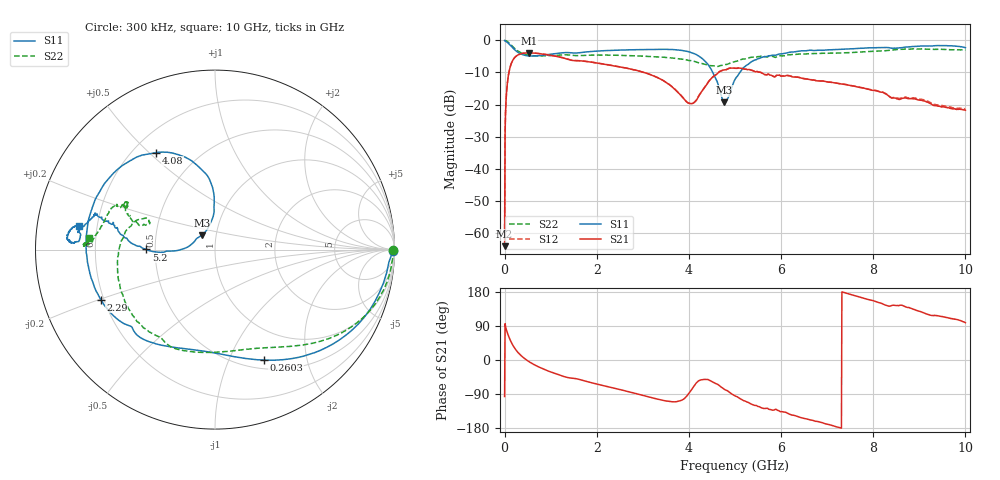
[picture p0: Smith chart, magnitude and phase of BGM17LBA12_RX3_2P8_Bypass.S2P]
!Agilent Technologies,E5071C,MY46316587,B.13.01
!Date: Fri Dec 08 10:57:01 2017
!Data & Calibration Information:
!Freq	S11:SOLT2(ON)	S21:SOLT2(ON)	S12:SOLT2(ON)	S22:SOLT2(ON)
!PortZ  Port1:50+j0  Port2:50+j0
!Above PortZ is port z conversion or system Z0 setting when saving the data.
!When reading, reference impedance value at option line is always used.
# Hz S dB R 50
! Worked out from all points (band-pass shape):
!   1001 points, 300 kHz to 10 GHz, reference 50 ohm
!   highest |S21| = -3.92 dB at 530.3 MHz (marker M1); lowest = -63.9 dB at 300 kHz (marker M2)
!   |S21| within 3 dB of the highest: 154.2 MHz to 1.932 GHz (1.777 GHz wide, 170 % of centre)
!   lowest |S11| = -19.3 dB at 4.77 GHz (marker M3), VSWR 1.24, Z = 42.7 + j6.97 ohm
!   |S11| at or under -10 dB: 4.518 GHz to 5.105 GHz (587.2 MHz wide, 12.2 % of centre)
!   |S22| runs from -8.2 to -0.1 dB; largest |S21 - S12| = 0.0059
!   S11 on the Smith chart (normalised r, x): 300 kHz: open; 260.3 MHz: 0.60, -1.35; 2.29 GHz: 0.19, -0.20; 4.08 GHz: 0.29, +0.53; 5.2 GHz: 0.45, +0.00; 10 GHz: 0.13, +0.09
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300000  -0.07 -0.3  -63.94 -96.5  -58.58 165.9  -0.06 -0.2
6.02982e7  -0.67 -21.2  -13.33 71.7  -13.25 71.8  -0.40 -16.0
7.02979e7  -0.79 -24.3  -12.11 68.3  -12.05 68.3  -0.50 -18.4
1.402958e8  -1.80 -43.6  -7.42 47.8  -7.38 47.7  -1.45 -33.1
2.602922e8  -3.45 -66.3  -4.85 24.3  -4.82 24.1  -3.06 -49.5
5.302841e8  -4.86 -93.5  -3.92 -4.4  -3.90 -4.5  -4.65 -71.5
1.030269e9  -4.28 -119.5  -4.75 -33.0  -4.73 -33.1  -4.73 -99.7
1.67025e9  -3.79 -139.5  -6.42 -52.9  -6.37 -52.9  -4.74 -123.8
2.290231e9  -3.16 -156.4  -7.74 -71.9  -7.72 -71.7  -4.63 -140.3
3.3402e9  -2.81 165.0  -11.74 -103.8  -11.76 -103.4  -5.19 -170.7
3.720188e9  -2.97 144.8  -15.60 -110.1  -15.55 -109.8  -5.61 174.6
4.080178e9  -3.98 121.3  -19.62 -74.2  -19.54 -74.0  -6.43 161.4
4.440167e9  -8.04 94.7  -12.57 -53.2  -12.58 -52.9  -7.86 156.0
4.770157e9  -19.28 132.1  -9.19 -77.5  -9.20 -77.5  -7.62 160.5
4.850154e9  -17.91 162.6  -8.84 -82.5  -8.82 -82.4  -7.35 161.6
5.00015e9  -12.16 -178.1  -8.72 -94.7  -8.70 -94.6  -6.63 160.8
5.200144e9  -8.33 179.9  -8.99 -107.7  -8.96 -107.7  -5.84 158.1
5.610132e9  -5.18 168.9  -10.36 -127.8  -10.32 -127.7  -4.92 152.3
6.6701e9  -3.13 163.0  -12.35 -158.9  -12.29 -158.6  -4.15 158.0
8.34005e9  -2.31 172.5  -17.40 141.9  -17.29 141.9  -3.13 177.1
8.890033e9  -1.92 177.3  -18.23 133.2  -17.88 133.1  -2.67 178.1
1e10  -2.30 169.9  -21.74 98.4  -21.43 99.1  -3.03 174.9
